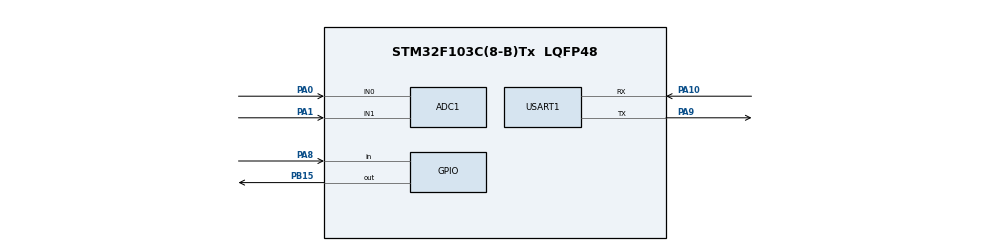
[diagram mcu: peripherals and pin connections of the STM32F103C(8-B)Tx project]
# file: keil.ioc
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ADC1.Channel-1\#ChannelRegularConversion=ADC_CHANNEL_0
ADC1.Channel-2\#ChannelRegularConversion=ADC_CHANNEL_1
ADC1.ContinuousConvMode=ENABLE
ADC1.EnableRegularConversion=ENABLE
ADC1.NbrOfConversion=2
ADC1.NbrOfConversionFlag=1
ADC1.Rank-1\#ChannelRegularConversion=1
ADC1.Rank-2\#ChannelRegularConversion=2
ADC1.SamplingTime-1\#ChannelRegularConversion=ADC_SAMPLETIME_239CYCLES_5
ADC1.SamplingTime-2\#ChannelRegularConversion=ADC_SAMPLETIME_239CYCLES_5
ADC1.master=1
Dma.ADC1.0.Direction=DMA_PERIPH_TO_MEMORY
Dma.ADC1.0.Instance=DMA1_Channel1
Dma.ADC1.0.MemDataAlignment=DMA_MDATAALIGN_HALFWORD
Dma.ADC1.0.MemInc=DMA_MINC_ENABLE
Dma.ADC1.0.Mode=DMA_NORMAL
Dma.ADC1.0.PeriphDataAlignment=DMA_PDATAALIGN_HALFWORD
Dma.ADC1.0.PeriphInc=DMA_PINC_DISABLE
Dma.ADC1.0.Priority=DMA_PRIORITY_LOW
Dma.Request0=ADC1
Mcu.Family=STM32F1
Mcu.Name=STM32F103C(8-B)Tx
Mcu.Package=LQFP48
NVIC.ADC1_2_IRQn=true\:0\:0\:false\:false\:true\:true\:true
NVIC.DMA1_Channel1_IRQn=true\:0\:0\:false\:false\:true\:false\:true
NVIC.PriorityGroup=NVIC_PRIORITYGROUP_4
NVIC.USART1_IRQn=true\:0\:0\:false\:false\:true\:true\:true
PA0-WKUP.Signal=ADCx_IN0
PA1.Signal=ADCx_IN1
PA10.Mode=Asynchronous
PA10.Signal=USART1_RX
PA13.Mode=JTAG_4_pins
PA13.Signal=SYS_JTMS-SWDIO
PA14.Mode=JTAG_4_pins
PA14.Signal=SYS_JTCK-SWCLK
PA15.Mode=JTAG_4_pins
PA15.Signal=SYS_JTDI
PA8.Signal=GPIO_Input
PA9.Mode=Asynchronous
PA9.Signal=USART1_TX
PB15.Signal=GPIO_Output
PB3.Mode=JTAG_4_pins
PB3.Signal=SYS_JTDO-TRACESWO
PD0-OSC_IN.Mode=HSE-External-Oscillator
PD0-OSC_IN.Signal=RCC_OSC_IN
PD1-OSC_OUT.Mode=HSE-External-Oscillator
PD1-OSC_OUT.Signal=RCC_OSC_OUT
ProjectManager.HeapSize=0x200
ProjectManager.StackSize=0x400
ProjectManager.TargetToolchain=MDK-ARM V5.27
RCC.ADCPresc=RCC_ADCPCLK2_DIV8
RCC.AHBFreq_Value=72000000
RCC.APB1CLKDivider=RCC_HCLK_DIV2
RCC.APB1Freq_Value=36000000
RCC.APB1TimFreq_Value=72000000
RCC.APB2CLKDivider=RCC_HCLK_DIV2
RCC.APB2Freq_Value=36000000
RCC.APB2TimFreq_Value=72000000
RCC.HCLKFreq_Value=72000000
RCC.PLLMUL=RCC_PLL_MUL9
RCC.PLLSourceVirtual=RCC_PLLSOURCE_HSE
RCC.SYSCLKFreq_VALUE=72000000
RCC.SYSCLKSource=RCC_SYSCLKSOURCE_PLLCLK
RCC.USBFreq_Value=72000000
SH.ADCx_IN0.0=ADC1_IN0,IN0
SH.ADCx_IN1.0=ADC1_IN1,IN1
USART1.VirtualMode=VM_ASYNC
board=custom

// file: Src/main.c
/* USER CODE BEGIN Header */
/**
  ******************************************************************************
  * @file           : main.c
  * @brief          : Main program body
  ******************************************************************************
  * @attention
  *
  * <h2><center>&copy; Copyright (c) 2020 STMicroelectronics.
  * All rights reserved.</center></h2>
  *
  * This software component is licensed by ST under BSD 3-Clause license,
  * the "License"; You may not use this file except in compliance with the
  * License. You may obtain a copy of the License at:
  *                        opensource.org/licenses/BSD-3-Clause
  *
  ******************************************************************************
  */
/* USER CODE END Header */

#include "main.h"

ADC_HandleTypeDef hadc1;
DMA_HandleTypeDef hdma_adc1;

UART_HandleTypeDef huart1;

void SystemClock_Config(void);
static void MX_GPIO_Init(void);
static void MX_DMA_Init(void);
static void MX_ADC1_Init(void);
static void MX_USART1_UART_Init(void);

int main(void)
{

  /* MCU Configuration--------------------------------------------------------*/

  /* Reset of all peripherals, Initializes the Flash interface and the Systick. */
  HAL_Init();

  /* Configure the system clock */
  SystemClock_Config();

  /* Initialize all configured peripherals */
  MX_GPIO_Init();
  MX_DMA_Init();
  MX_ADC1_Init();
  MX_USART1_UART_Init();

  /* Infinite loop */
  while (1)
  {

  }
}

void SystemClock_Config(void)
{
  RCC_OscInitTypeDef RCC_OscInitStruct = {0};
  RCC_ClkInitTypeDef RCC_ClkInitStruct = {0};
  RCC_PeriphCLKInitTypeDef PeriphClkInit = {0};

  /** Initializes the CPU, AHB and APB busses clocks
  */
  RCC_OscInitStruct.OscillatorType = RCC_OSCILLATORTYPE_HSE;
  RCC_OscInitStruct.HSEState = RCC_HSE_ON;
  RCC_OscInitStruct.HSEPredivValue = RCC_HSE_PREDIV_DIV1;
  RCC_OscInitStruct.HSIState = RCC_HSI_ON;
  RCC_OscInitStruct.PLL.PLLState = RCC_PLL_ON;
  RCC_OscInitStruct.PLL.PLLSource = RCC_PLLSOURCE_HSE;
  RCC_OscInitStruct.PLL.PLLMUL = RCC_PLL_MUL9;
  if (HAL_RCC_OscConfig(&RCC_OscInitStruct) != HAL_OK)
  {
    Error_Handler();
  }
  /** Initializes the CPU, AHB and APB busses clocks
  */
  RCC_ClkInitStruct.ClockType = RCC_CLOCKTYPE_HCLK|RCC_CLOCKTYPE_SYSCLK
                              |RCC_CLOCKTYPE_PCLK1|RCC_CLOCKTYPE_PCLK2;
  RCC_ClkInitStruct.SYSCLKSource = RCC_SYSCLKSOURCE_PLLCLK;
  RCC_ClkInitStruct.AHBCLKDivider = RCC_SYSCLK_DIV1;
  RCC_ClkInitStruct.APB1CLKDivider = RCC_HCLK_DIV2;
  RCC_ClkInitStruct.APB2CLKDivider = RCC_HCLK_DIV1;

  if (HAL_RCC_ClockConfig(&RCC_ClkInitStruct, FLASH_LATENCY_2) != HAL_OK)
  {
    Error_Handler();
  }
  PeriphClkInit.PeriphClockSelection = RCC_PERIPHCLK_ADC;
  PeriphClkInit.AdcClockSelection = RCC_ADCPCLK2_DIV8;
  if (HAL_RCCEx_PeriphCLKConfig(&PeriphClkInit) != HAL_OK)
  {
    Error_Handler();
  }
}

static void MX_ADC1_Init(void)
{

  ADC_ChannelConfTypeDef sConfig = {0};

  /** Common config
  */
  hadc1.Instance = ADC1;
  hadc1.Init.ScanConvMode = ADC_SCAN_ENABLE;
  hadc1.Init.ContinuousConvMode = ENABLE;
  hadc1.Init.DiscontinuousConvMode = DISABLE;
  hadc1.Init.ExternalTrigConv = ADC_SOFTWARE_START;
  hadc1.Init.DataAlign = ADC_DATAALIGN_RIGHT;
  hadc1.Init.NbrOfConversion = 2;
  if (HAL_ADC_Init(&hadc1) != HAL_OK)
  {
    Error_Handler();
  }
  /** Configure Regular Channel
  */
  sConfig.Channel = ADC_CHANNEL_0;
  sConfig.Rank = ADC_REGULAR_RANK_1;
  sConfig.SamplingTime = ADC_SAMPLETIME_239CYCLES_5;
  if (HAL_ADC_ConfigChannel(&hadc1, &sConfig) != HAL_OK)
  {
    Error_Handler();
  }
  /** Configure Regular Channel
  */
  sConfig.Channel = ADC_CHANNEL_1;
  sConfig.Rank = ADC_REGULAR_RANK_2;
  if (HAL_ADC_ConfigChannel(&hadc1, &sConfig) != HAL_OK)
  {
    Error_Handler();
  }

}

static void MX_USART1_UART_Init(void)
{

  huart1.Instance = USART1;
  huart1.Init.BaudRate = 115200;
  huart1.Init.WordLength = UART_WORDLENGTH_8B;
  huart1.Init.StopBits = UART_STOPBITS_1;
  huart1.Init.Parity = UART_PARITY_NONE;
  huart1.Init.Mode = UART_MODE_TX_RX;
  huart1.Init.HwFlowCtl = UART_HWCONTROL_NONE;
  huart1.Init.OverSampling = UART_OVERSAMPLING_16;
  if (HAL_UART_Init(&huart1) != HAL_OK)
  {
    Error_Handler();
  }

}

static void MX_DMA_Init(void)
{

  /* DMA controller clock enable */
  __HAL_RCC_DMA1_CLK_ENABLE();

  /* DMA interrupt init */
  /* DMA1_Channel1_IRQn interrupt configuration */
  HAL_NVIC_SetPriority(DMA1_Channel1_IRQn, 0, 0);
  HAL_NVIC_EnableIRQ(DMA1_Channel1_IRQn);

}

static void MX_GPIO_Init(void)
{
  GPIO_InitTypeDef GPIO_InitStruct = {0};

  /* GPIO Ports Clock Enable */
  __HAL_RCC_GPIOD_CLK_ENABLE();
  __HAL_RCC_GPIOA_CLK_ENABLE();
  __HAL_RCC_GPIOB_CLK_ENABLE();

  /*Configure GPIO pin Output Level */
  HAL_GPIO_WritePin(GPIOB, GPIO_PIN_15, GPIO_PIN_RESET);

  /*Configure GPIO pin : PB15 */
  GPIO_InitStruct.Pin = GPIO_PIN_15;
  GPIO_InitStruct.Mode = GPIO_MODE_OUTPUT_PP;
  GPIO_InitStruct.Pull = GPIO_NOPULL;
  GPIO_InitStruct.Speed = GPIO_SPEED_FREQ_LOW;
  HAL_GPIO_Init(GPIOB, &GPIO_InitStruct);

  /*Configure GPIO pin : PA8 */
  GPIO_InitStruct.Pin = GPIO_PIN_8;
  GPIO_InitStruct.Mode = GPIO_MODE_INPUT;
  GPIO_InitStruct.Pull = GPIO_NOPULL;
  HAL_GPIO_Init(GPIOA, &GPIO_InitStruct);

}

void Error_Handler(void)
{
}

/************************ (C) COPYRIGHT STMicroelectronics *****END OF FILE****/
